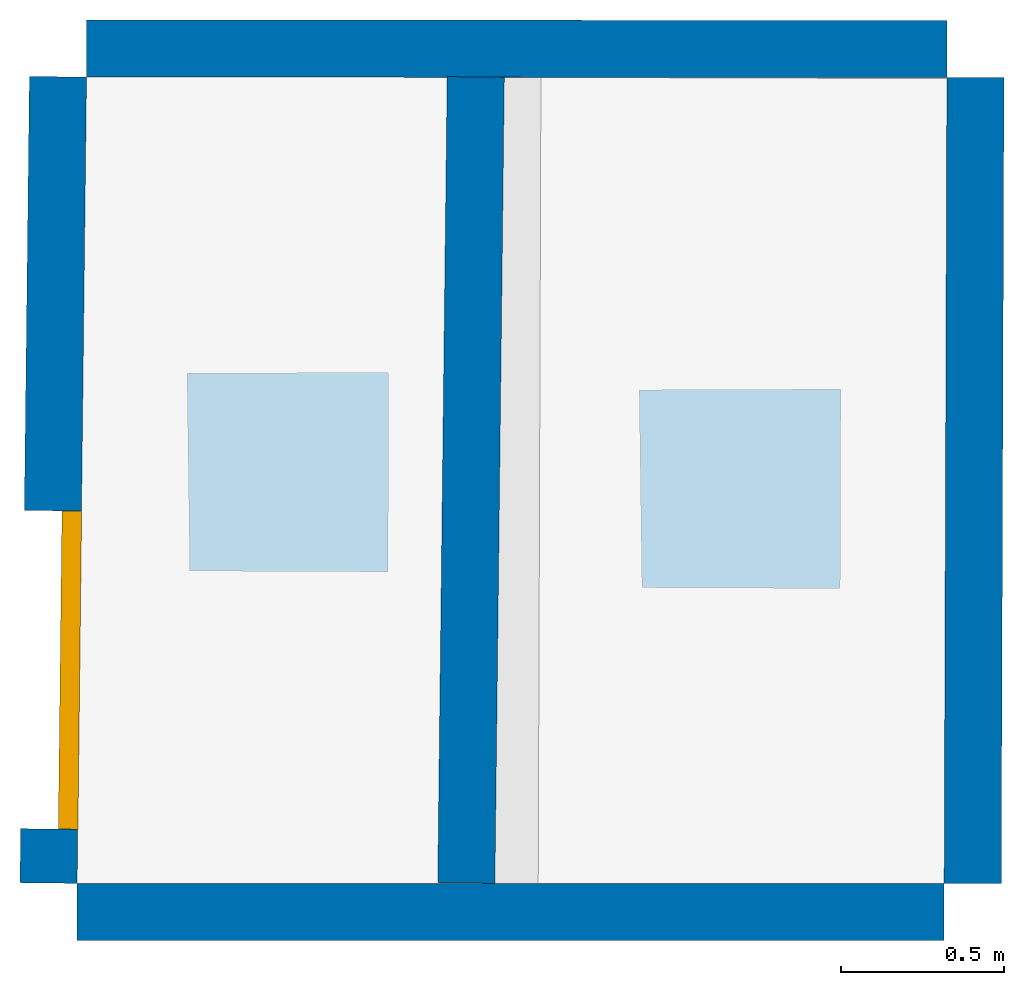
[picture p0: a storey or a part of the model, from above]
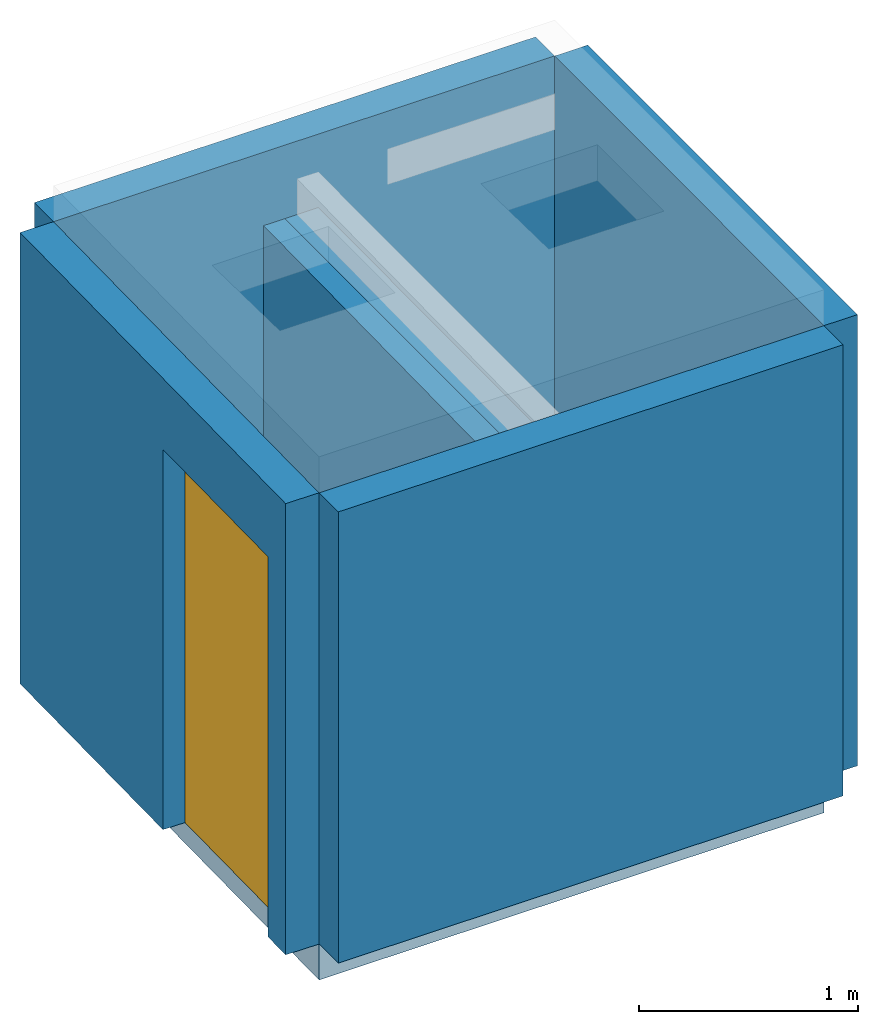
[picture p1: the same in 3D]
Properties of the parts of a building model (IFC2X3)

# File
Description: ViewDefinition[CoordinationView_V2.0]
File name: C:\Users\p.steinmetzer\Documents\IFC Query\Exporte\Visoft neu files\Bad zwischenwände.ifc
Time: 2021-04-15T11:52:22
Written by: IFC 2x3 writer version 1.1
Made in: IFCExportDemo.exe

# IfcBuildingStorey, 600 EG
In: Gebäude
Elevation: 0 m

# IfcDoor, Door
In: 600 EG
OverallHeight: 2.11581 m; OverallWidth: 0.975601 m

# IfcSlab (3)
In: 600 EG
PredefinedType: FLOOR
Name
Ground
2 x Ceiling
